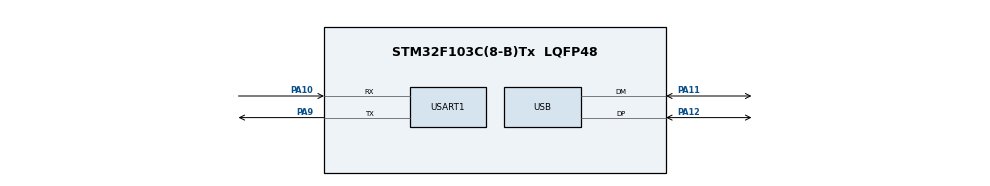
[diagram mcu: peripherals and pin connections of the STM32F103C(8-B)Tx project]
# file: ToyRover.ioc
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FREERTOS.Tasks01=defaultTask,24,128,StartDefaultTask,Default,NULL,Dynamic,NULL,NULL
FREERTOS.configUSE_NEWLIB_REENTRANT=1
Mcu.Family=STM32F1
Mcu.Name=STM32F103C(8-B)Tx
Mcu.Package=LQFP48
NVIC.PriorityGroup=NVIC_PRIORITYGROUP_4
NVIC.TIM2_IRQn=true\:15\:0\:false\:false\:true\:false\:false\:true\:true
NVIC.TimeBase=TIM2_IRQn
NVIC.TimeBaseIP=TIM2
PA10.Mode=Asynchronous
PA10.Signal=USART1_RX
PA11.Mode=Device
PA11.Signal=USB_DM
PA12.Mode=Device
PA12.Signal=USB_DP
PA13.Mode=Trace_Asynchronous_SW
PA13.Signal=SYS_JTMS-SWDIO
PA14.Mode=Trace_Asynchronous_SW
PA14.Signal=SYS_JTCK-SWCLK
PA9.Mode=Asynchronous
PA9.Signal=USART1_TX
PB3.Mode=Trace_Asynchronous_SW
PB3.Signal=SYS_JTDO-TRACESWO
PD0-OSC_IN.Mode=HSE-External-Oscillator
PD0-OSC_IN.Signal=RCC_OSC_IN
PD1-OSC_OUT.Mode=HSE-External-Oscillator
PD1-OSC_OUT.Signal=RCC_OSC_OUT
ProjectManager.HeapSize=0x200
ProjectManager.StackSize=0x400
ProjectManager.TargetToolchain=CMake
RCC.AHBCLKDivider=RCC_SYSCLK_DIV2
RCC.AHBFreq_Value=36000000
RCC.APB1CLKDivider=RCC_HCLK_DIV2
RCC.APB1Freq_Value=18000000
RCC.APB1TimFreq_Value=36000000
RCC.APB2Freq_Value=36000000
RCC.APB2TimFreq_Value=36000000
RCC.EnbaleCSS=true
RCC.HCLKFreq_Value=36000000
RCC.PLLMUL=RCC_PLL_MUL9
RCC.SYSCLKFreq_VALUE=72000000
RCC.SYSCLKSource=RCC_SYSCLKSOURCE_PLLCLK
RCC.USBFreq_Value=48000000
RCC.USBPrescaler=RCC_USBCLKSOURCE_PLL_DIV1_5
USART1.VirtualMode=VM_ASYNC
VP_FREERTOS_VS_CMSIS_V2.Mode=CMSIS_V2
VP_SYS_VS_tim2.Mode=TIM2
board=custom

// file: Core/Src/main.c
/* USER CODE BEGIN Header */
/**
  ******************************************************************************
  * @file           : main.c
  * @brief          : Main program body
  ******************************************************************************
  * @attention
  *
  * Copyright (c) 2026 STMicroelectronics.
  * All rights reserved.
  *
  * This software is licensed under terms that can be found in the LICENSE file
  * in the root directory of this software component.
  * If no LICENSE file comes with this software, it is provided AS-IS.
  *
  ******************************************************************************
  */
/* USER CODE END Header */
#include "main.h"
#include "cmsis_os.h"

/* USER CODE BEGIN Includes */
#include <stdio.h>
#include "protocol.h"
#include "proto_cmd.h"
#include "diff_drive.h"
#include "platform.h"
#include "usb_cdc.h"
/* USER CODE END Includes */

UART_HandleTypeDef huart1;

PCD_HandleTypeDef hpcd_USB_FS;

/* Definitions for defaultTask */
osThreadId_t defaultTaskHandle;
const osThreadAttr_t defaultTask_attributes = {
  .name = "defaultTask",
  .stack_size = 128 * 4,
  .priority = (osPriority_t) osPriorityNormal,
};
/* USER CODE BEGIN PV */
static proto_sys_ctx_t       g_proto_ctx;
static diff_drive_params_t   g_drive_params;
static volatile uint8_t      g_uart_rx_byte;  /* UART RX interrupt buffer */
/* USER CODE END PV */

void SystemClock_Config(void);
static void MX_GPIO_Init(void);
static void MX_USART1_UART_Init(void);
static void MX_USB_PCD_Init(void);
void StartDefaultTask(void *argument);

/* USER CODE BEGIN PFP */
static void proto_handler(const proto_cmd_t *cmd);
/* USER CODE END PFP */

int main(void)
{

  /* MCU Configuration--------------------------------------------------------*/

  /* Reset of all peripherals, Initializes the Flash interface and the Systick. */
  HAL_Init();

  /* Configure the system clock */
  SystemClock_Config();

  /* Initialize all configured peripherals */
  MX_GPIO_Init();
  MX_USART1_UART_Init();
  MX_USB_PCD_Init();
  /* USER CODE BEGIN 2 */
  /* SWO output via PB3 — async NRZ, 1 MHz.
   * After HAL_MspInit runs SWJ_NOJTAG, PB3 becomes GPIO.
   * Must set it as AF push-pull before enabling trace. */
  GPIOB->CRL &= ~(0xFUL << 12);             /* PB3: clear CNF+MODE */
  GPIOB->CRL |=  (0xBUL << 12);             /* PB3: AF push-pull, 50 MHz */

  /* Enable global trace clock — required before any TPIU/ITM access */
  CoreDebug->DEMCR |= CoreDebug_DEMCR_TRCENA_Msk;
  __DSB();

  /* Unlock TPIU registers (LAR at TPI_BASE + 0xFB0) */
  *((volatile uint32_t *)(TPI_BASE + 0xFB0)) = 0xC5ACCE55;
  /* Unlock ITM registers (silently ignored if not unlocked!) */
  ITM->LAR = 0xC5ACCE55;

  /* TPIU: async NRZ, 500 kHz from SYSCLK (72 MHz).
   * FFCR left at default 0 — no continuous formatting, output only when data. */
  TPI->ACPR   = 143;                        /* 72 MHz / 500 kHz - 1 */
  TPI->SPPR   = 2;                          /* NRZ */

  /* Route trace to PB3 — explicitly clear TRACE_MODE (async) */
  DBGMCU->CR &= ~DBGMCU_CR_TRACE_MODE_Msk;
  DBGMCU->CR |= DBGMCU_CR_TRACE_IOEN;

  /* ITM: enable, SWO mode, stimulus port 0 */
  ITM->TCR    = ITM_TCR_ITMENA_Msk | ITM_TCR_SWOENA_Msk;
  ITM->TER    = 1;
  __DSB();

  /* Direct stimulus write — bypass printf, tests hardware */
  ITM->PORT[0].u8 = 'A';
  ITM->PORT[0].u8 = '\n';

  printf("ToyRover booting...\r\n");

  /* ---- USB clock diagnostic ---- */
  printf("[CLK] HSE RDY=%d HSI RDY=%d PLL RDY=%d\r\n",
         (RCC->CR & RCC_CR_HSERDY) ? 1 : 0,
         (RCC->CR & RCC_CR_HSIRDY) ? 1 : 0,
         (RCC->CR & RCC_CR_PLLRDY) ? 1 : 0);
  {
    uint32_t sw = (RCC->CFGR & RCC_CFGR_SWS_Msk) >> RCC_CFGR_SWS_Pos;
    printf("[CLK] SYSCLK src=%s freq=%lu Hz\r\n",
           sw == 0 ? "HSI" : sw == 2 ? "PLL" : "?",
           (unsigned long)HAL_RCC_GetSysClockFreq());
  }

  /* ---- Protocol stack init ---- */
  diff_drive_init(&g_drive_params, 15.0f); /* 15cm wheel track — calibrate me */
  proto_cmd_init(&g_proto_ctx, platform_send_frame);
  proto_cmd_set_drive_params(&g_drive_params);
  protocol_reset();

  /* ---- UART RX for BLE module (MLT-BT05 @9600) ---- */
  HAL_UART_Receive_IT(&huart1, (uint8_t *)&g_uart_rx_byte, 1);
  printf("Protocol + UART RX ready (BLE)\r\n");
  /* USER CODE END 2 */

  /* Init scheduler */
  osKernelInitialize();

  /* Create the thread(s) */
  /* creation of defaultTask */
  defaultTaskHandle = osThreadNew(StartDefaultTask, NULL, &defaultTask_attributes);

  /* Start scheduler */
  osKernelStart();

  /* We should never get here as control is now taken by the scheduler */

  /* Infinite loop */
  while (1)
  {

  }
}

void SystemClock_Config(void)
{
  RCC_OscInitTypeDef RCC_OscInitStruct = {0};
  RCC_ClkInitTypeDef RCC_ClkInitStruct = {0};
  RCC_PeriphCLKInitTypeDef PeriphClkInit = {0};

  /** Initializes the RCC Oscillators according to the specified parameters
  * in the RCC_OscInitTypeDef structure.
  */
  RCC_OscInitStruct.OscillatorType = RCC_OSCILLATORTYPE_HSE;
  RCC_OscInitStruct.HSEState = RCC_HSE_ON;
  RCC_OscInitStruct.HSEPredivValue = RCC_HSE_PREDIV_DIV1;
  RCC_OscInitStruct.HSIState = RCC_HSI_ON;
  RCC_OscInitStruct.PLL.PLLState = RCC_PLL_ON;
  RCC_OscInitStruct.PLL.PLLSource = RCC_PLLSOURCE_HSE;
  RCC_OscInitStruct.PLL.PLLMUL = RCC_PLL_MUL9;
  if (HAL_RCC_OscConfig(&RCC_OscInitStruct) != HAL_OK)
  {
    Error_Handler();
  }

  /** Initializes the CPU, AHB and APB buses clocks
  */
  RCC_ClkInitStruct.ClockType = RCC_CLOCKTYPE_HCLK|RCC_CLOCKTYPE_SYSCLK
                              |RCC_CLOCKTYPE_PCLK1|RCC_CLOCKTYPE_PCLK2;
  RCC_ClkInitStruct.SYSCLKSource = RCC_SYSCLKSOURCE_PLLCLK;
  RCC_ClkInitStruct.AHBCLKDivider = RCC_SYSCLK_DIV1;
  RCC_ClkInitStruct.APB1CLKDivider = RCC_HCLK_DIV2;
  RCC_ClkInitStruct.APB2CLKDivider = RCC_HCLK_DIV1;

  if (HAL_RCC_ClockConfig(&RCC_ClkInitStruct, FLASH_LATENCY_2) != HAL_OK)
  {
    Error_Handler();
  }
  PeriphClkInit.PeriphClockSelection = RCC_PERIPHCLK_USB;
  PeriphClkInit.UsbClockSelection = RCC_USBCLKSOURCE_PLL_DIV1_5;
  if (HAL_RCCEx_PeriphCLKConfig(&PeriphClkInit) != HAL_OK)
  {
    Error_Handler();
  }

  /** Enables the Clock Security System
  */
  HAL_RCC_EnableCSS();
}

static void MX_USART1_UART_Init(void)
{

  huart1.Instance = USART1;
  huart1.Init.BaudRate = 9600;
  huart1.Init.WordLength = UART_WORDLENGTH_8B;
  huart1.Init.StopBits = UART_STOPBITS_1;
  huart1.Init.Parity = UART_PARITY_NONE;
  huart1.Init.Mode = UART_MODE_TX_RX;
  huart1.Init.HwFlowCtl = UART_HWCONTROL_NONE;
  huart1.Init.OverSampling = UART_OVERSAMPLING_16;
  if (HAL_UART_Init(&huart1) != HAL_OK)
  {
    Error_Handler();
  }

}

static void MX_USB_PCD_Init(void)
{

  hpcd_USB_FS.Instance = USB;
  hpcd_USB_FS.Init.dev_endpoints = 8;
  hpcd_USB_FS.Init.speed = PCD_SPEED_FULL;
  hpcd_USB_FS.Init.low_power_enable = DISABLE;
  hpcd_USB_FS.Init.lpm_enable = DISABLE;
  hpcd_USB_FS.Init.battery_charging_enable = DISABLE;
  if (HAL_PCD_Init(&hpcd_USB_FS) != HAL_OK)
  {
    Error_Handler();
  }

}

static void MX_GPIO_Init(void)
{

  /* GPIO Ports Clock Enable */
  __HAL_RCC_GPIOD_CLK_ENABLE();
  __HAL_RCC_GPIOA_CLK_ENABLE();
  __HAL_RCC_GPIOB_CLK_ENABLE();

}

/* USER CODE BEGIN 4 */

int __io_putchar(int ch)
{
  ITM_SendChar(ch);
  return ch;
}

/* ---- Protocol wrappers ---- */

static void proto_handler(const proto_cmd_t *cmd)
{
    /* Decode and log command with parameters */
    switch (cmd->cmd) {
    case CMD_MOVE: {
        cmd_move_t mv;
        if (protocol_parse_move(cmd, &mv)) {
            printf("[CMD] MOVE dir=%s speed=%d%%",
                   mv.direction == DIR_FORWARD ? "FWD" : "BWD", mv.speed);
            if (mv.duration_ms > 0) {
                printf(" dur=%ums", mv.duration_ms);
            } else {
                printf(" dur=continuous");
            }
            printf("\r\n");
        } else {
            printf("[CMD] MOVE (bad payload len=%d)\r\n", cmd->payload_len);
        }
        break;
    }
    case CMD_TURN: {
        cmd_turn_t tn;
        if (protocol_parse_turn(cmd, &tn)) {
            printf("[CMD] TURN %s angle=%d deg speed=%d%%\r\n",
                   tn.direction == TURN_LEFT ? "LEFT" : "RIGHT",
                   tn.angle, tn.speed);
        } else {
            printf("[CMD] TURN (bad payload len=%d)\r\n", cmd->payload_len);
        }
        break;
    }
    case CMD_ARC: {
        cmd_arc_t arc;
        if (protocol_parse_arc(cmd, &arc)) {
            printf("[CMD] ARC dir=%s %s speed=%d%% radius=%dcm\r\n",
                   arc.direction == DIR_FORWARD ? "FWD" : "BWD",
                   arc.turn_dir == TURN_LEFT ? "LEFT" : "RIGHT",
                   arc.speed, arc.radius_cm);
        } else {
            printf("[CMD] ARC (bad payload len=%d)\r\n", cmd->payload_len);
        }
        break;
    }
    case CMD_STOP:
        printf("[CMD] STOP\r\n");
        break;
    case CMD_HEARTBEAT: {
        cmd_heartbeat_t hb;
        if (protocol_parse_heartbeat(cmd, &hb)) {
            printf("[CMD] HEARTBEAT seq=%d\r\n", hb.seq);
        } else {
            printf("[CMD] HEARTBEAT (bad payload)\r\n");
        }
        break;
    }
    default:
        printf("[CMD] UNKNOWN 0x%02X len=%d\r\n", cmd->cmd, cmd->payload_len);
        break;
    }
    proto_cmd_dispatch(&g_proto_ctx, cmd);
}

static void feed_rx_byte(uint8_t byte)
{
    uint32_t now = platform_get_tick_ms();
    proto_cmd_set_tick(&g_proto_ctx, now);
    protocol_feed_byte(byte, proto_handler);
}

/* ---- HAL UART RX callback ---- */
void HAL_UART_RxCpltCallback(UART_HandleTypeDef *huart)
{
    if (huart->Instance == USART1) {
        feed_rx_byte(g_uart_rx_byte);
        HAL_UART_Receive_IT(&huart1, (uint8_t *)&g_uart_rx_byte, 1);
    }
}

/* USER CODE END 4 */

void StartDefaultTask(void *argument)
{
  /* USER CODE BEGIN 5 */
  /* Infinite loop — protocol maintenance every 100ms,
   * with debug heartbeat every ~2 seconds */
  int tick = 0;
  for(;;)
  {
    uint32_t now = platform_get_tick_ms();
    proto_cmd_heartbeat_check(&g_proto_ctx, now);
    proto_cmd_timer_check(&g_proto_ctx, now);

    tick++;
    if (tick >= 20) {
        tick = 0;
    }
    osDelay(pdMS_TO_TICKS(100));
  }
  /* USER CODE END 5 */
}

void HAL_TIM_PeriodElapsedCallback(TIM_HandleTypeDef *htim)
{
  if (htim->Instance == TIM2)
  {
    HAL_IncTick();
  }
}

void Error_Handler(void)
{
  __disable_irq();
  while (1)
  {
  }
}
